# Confidential Information of ARM, Inc.
# Use subject to ARM license.
# Copyright (c) 2018 ARM, Inc.

# ACI Version r9p1

# Reifier 3.1.1

VERSION 5.6 ;

BUSBITCHARS "[]" ;

#name: High Speed Two Port RF RVT-HVT-RVT Compiler|40G 40nm Process, 0.741^2 BitCell
#version: r9p1
#comment: 
#configuration:  -instname "rf_2p_hse" -words 64 -bits 16 -frequency 100 -mux 1 -pipeline off -write_mask off -wp_size 8 -top_layer "m5-m9" -power_type otc -redundancy off -rcols 1 -rrows 0 -bmux on -ser none -power_gating off -retention on -ema on -atf off -cust_comment "" -bus_notation on -left_bus_delim "[" -right_bus_delim "]" -pwr_gnd_rename "vddpe:VDDPE,vddce:VDDCE,vsse:VSSE" -prefix "" -name_case upper -check_instname on -diodes on -drive 4 -corners ss_0p81v_0p81v_125c,ss_0p81v_0p81v_m40c,ffg_0p99v_0p99v_125c,ff_0p99v_0p99v_125c,ff_0p99v_0p99v_m40c,tt_0p90v_0p90v_25c
SITE rf_2p_hse
  CLASS  CORE ;
  SIZE 75.34 BY 48.695 ;
  END rf_2p_hse

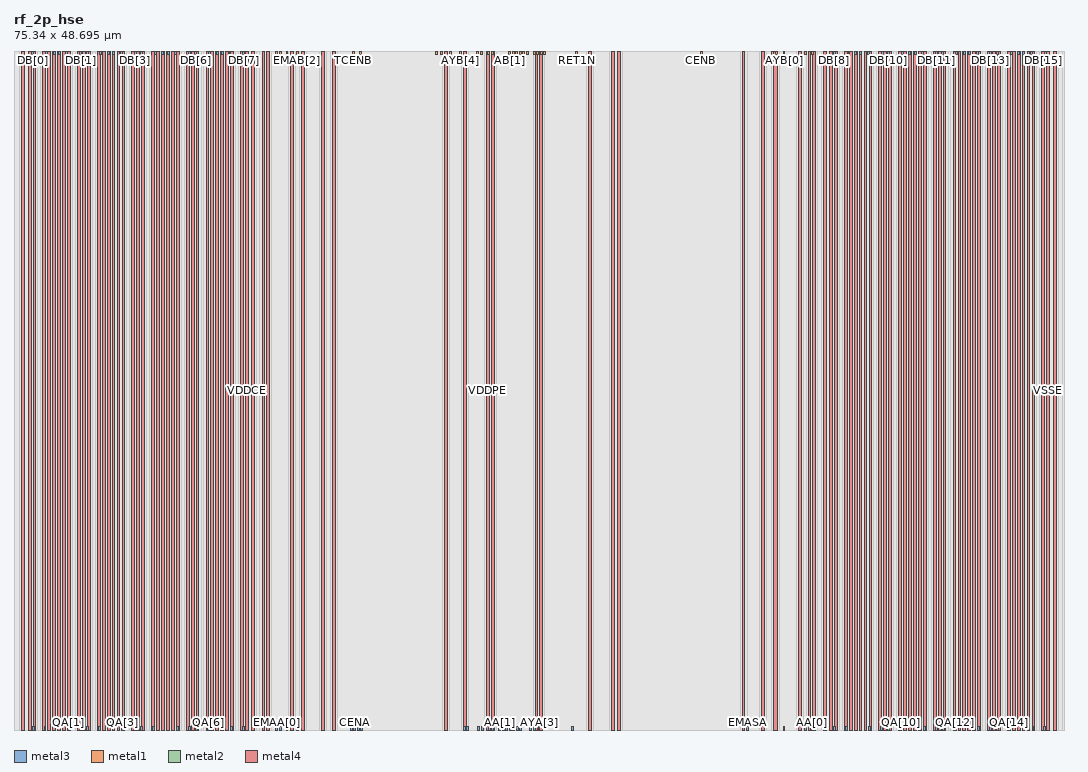
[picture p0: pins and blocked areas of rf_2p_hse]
MACRO rf_2p_hse
  FOREIGN rf_2p_hse 0 0 ;
  SYMMETRY X Y R90 ;
  SITE rf_2p_hse ;
  SIZE 75.34 BY 48.695 ;
  CLASS BLOCK ;
  PIN TDB[13]
    DIRECTION INPUT ;
    USE SIGNAL ;
    SHAPE ABUTMENT ;
    PORT
      LAYER metal3 ;
      RECT 68.49 48.445 68.63 48.695 ;
      END
    ANTENNAGATEAREA 0.009 ;
    ANTENNADIFFAREA 0.035 ;
    END TDB[13]
  PIN TDB[12]
    DIRECTION INPUT ;
    USE SIGNAL ;
    SHAPE ABUTMENT ;
    PORT
      LAYER metal3 ;
      RECT 68.11 48.445 68.25 48.695 ;
      END
    ANTENNAGATEAREA 0.009 ;
    ANTENNADIFFAREA 0.035 ;
    END TDB[12]
  PIN DYB[13]
    DIRECTION OUTPUT ;
    USE SIGNAL ;
    SHAPE ABUTMENT ;
    PORT
      LAYER metal3 ;
      RECT 69.03 48.445 69.17 48.695 ;
      END
    ANTENNADIFFAREA 0.035 ;
    END DYB[13]
  PIN DYB[12]
    DIRECTION OUTPUT ;
    USE SIGNAL ;
    SHAPE ABUTMENT ;
    PORT
      LAYER metal3 ;
      RECT 67.57 48.445 67.71 48.695 ;
      END
    ANTENNADIFFAREA 0.035 ;
    END DYB[12]
  PIN DB[13]
    DIRECTION INPUT ;
    USE SIGNAL ;
    SHAPE ABUTMENT ;
    PORT
      LAYER metal3 ;
      RECT 70.03 48.445 70.17 48.695 ;
      END
    ANTENNAGATEAREA 0.009 ;
    ANTENNADIFFAREA 0.035 ;
    END DB[13]
  PIN DB[12]
    DIRECTION INPUT ;
    USE SIGNAL ;
    SHAPE ABUTMENT ;
    PORT
      LAYER metal3 ;
      RECT 66.57 48.445 66.71 48.695 ;
      END
    ANTENNAGATEAREA 0.009 ;
    ANTENNADIFFAREA 0.035 ;
    END DB[12]
  PIN DB[14]
    DIRECTION INPUT ;
    USE SIGNAL ;
    SHAPE ABUTMENT ;
    PORT
      LAYER metal3 ;
      RECT 70.47 48.445 70.61 48.695 ;
      END
    ANTENNAGATEAREA 0.009 ;
    ANTENNADIFFAREA 0.035 ;
    END DB[14]
  PIN DB[11]
    DIRECTION INPUT ;
    USE SIGNAL ;
    SHAPE ABUTMENT ;
    PORT
      LAYER metal3 ;
      RECT 66.13 48.445 66.27 48.695 ;
      END
    ANTENNAGATEAREA 0.009 ;
    ANTENNADIFFAREA 0.035 ;
    END DB[11]
  PIN DYB[14]
    DIRECTION OUTPUT ;
    USE SIGNAL ;
    SHAPE ABUTMENT ;
    PORT
      LAYER metal3 ;
      RECT 71.47 48.445 71.61 48.695 ;
      END
    ANTENNADIFFAREA 0.035 ;
    END DYB[14]
  PIN DYB[11]
    DIRECTION OUTPUT ;
    USE SIGNAL ;
    SHAPE ABUTMENT ;
    PORT
      LAYER metal3 ;
      RECT 65.13 48.445 65.27 48.695 ;
      END
    ANTENNADIFFAREA 0.035 ;
    END DYB[11]
  PIN TDB[14]
    DIRECTION INPUT ;
    USE SIGNAL ;
    SHAPE ABUTMENT ;
    PORT
      LAYER metal3 ;
      RECT 72.01 48.445 72.15 48.695 ;
      END
    ANTENNAGATEAREA 0.009 ;
    ANTENNADIFFAREA 0.035 ;
    END TDB[14]
  PIN TDB[11]
    DIRECTION INPUT ;
    USE SIGNAL ;
    SHAPE ABUTMENT ;
    PORT
      LAYER metal3 ;
      RECT 64.59 48.445 64.73 48.695 ;
      END
    ANTENNAGATEAREA 0.009 ;
    ANTENNADIFFAREA 0.035 ;
    END TDB[11]
  PIN TDB[15]
    DIRECTION INPUT ;
    USE SIGNAL ;
    SHAPE ABUTMENT ;
    PORT
      LAYER metal3 ;
      RECT 72.39 48.445 72.53 48.695 ;
      END
    ANTENNAGATEAREA 0.009 ;
    ANTENNADIFFAREA 0.035 ;
    END TDB[15]
  PIN TDB[10]
    DIRECTION INPUT ;
    USE SIGNAL ;
    SHAPE ABUTMENT ;
    PORT
      LAYER metal3 ;
      RECT 64.21 48.445 64.35 48.695 ;
      END
    ANTENNAGATEAREA 0.009 ;
    ANTENNADIFFAREA 0.035 ;
    END TDB[10]
  PIN DYB[15]
    DIRECTION OUTPUT ;
    USE SIGNAL ;
    SHAPE ABUTMENT ;
    PORT
      LAYER metal3 ;
      RECT 72.93 48.445 73.07 48.695 ;
      END
    ANTENNADIFFAREA 0.035 ;
    END DYB[15]
  PIN DYB[10]
    DIRECTION OUTPUT ;
    USE SIGNAL ;
    SHAPE ABUTMENT ;
    PORT
      LAYER metal3 ;
      RECT 63.67 48.445 63.81 48.695 ;
      END
    ANTENNADIFFAREA 0.035 ;
    END DYB[10]
  PIN DB[15]
    DIRECTION INPUT ;
    USE SIGNAL ;
    SHAPE ABUTMENT ;
    PORT
      LAYER metal3 ;
      RECT 73.93 48.445 74.07 48.695 ;
      END
    ANTENNAGATEAREA 0.009 ;
    ANTENNADIFFAREA 0.035 ;
    END DB[15]
  PIN DB[10]
    DIRECTION INPUT ;
    USE SIGNAL ;
    SHAPE ABUTMENT ;
    PORT
      LAYER metal3 ;
      RECT 62.67 48.445 62.81 48.695 ;
      END
    ANTENNAGATEAREA 0.009 ;
    ANTENNADIFFAREA 0.035 ;
    END DB[10]
  PIN TQA[0]
    DIRECTION INPUT ;
    USE SIGNAL ;
    SHAPE ABUTMENT ;
    PORT
      LAYER metal1 ;
      RECT 1.3 0.0 1.44 0.25 ;
      LAYER metal2 ;
      RECT 1.3 0.0 1.44 0.25 ;
      LAYER metal3 ;
      RECT 1.3 0.0 1.44 0.25 ;
      END
    ANTENNAGATEAREA 0.009 ;
    ANTENNADIFFAREA 0.035 ;
    END TQA[0]
  PIN DB[9]
    DIRECTION INPUT ;
    USE SIGNAL ;
    SHAPE ABUTMENT ;
    PORT
      LAYER metal3 ;
      RECT 62.23 48.445 62.37 48.695 ;
      END
    ANTENNAGATEAREA 0.009 ;
    ANTENNADIFFAREA 0.035 ;
    END DB[9]
  PIN QA[0]
    DIRECTION OUTPUT ;
    USE SIGNAL ;
    SHAPE ABUTMENT ;
    PORT
      LAYER metal1 ;
      RECT 2.155 0.0 2.295 0.25 ;
      LAYER metal2 ;
      RECT 2.155 0.0 2.295 0.25 ;
      LAYER metal3 ;
      RECT 2.155 0.0 2.295 0.25 ;
      END
    ANTENNADIFFAREA 0.035 ;
    END QA[0]
  PIN DYB[9]
    DIRECTION OUTPUT ;
    USE SIGNAL ;
    SHAPE ABUTMENT ;
    PORT
      LAYER metal3 ;
      RECT 61.23 48.445 61.37 48.695 ;
      END
    ANTENNADIFFAREA 0.035 ;
    END DYB[9]
  PIN QA[1]
    DIRECTION OUTPUT ;
    USE SIGNAL ;
    SHAPE ABUTMENT ;
    PORT
      LAYER metal1 ;
      RECT 3.845 0.0 3.985 0.25 ;
      LAYER metal2 ;
      RECT 3.845 0.0 3.985 0.25 ;
      LAYER metal3 ;
      RECT 3.845 0.0 3.985 0.25 ;
      END
    ANTENNADIFFAREA 0.035 ;
    END QA[1]
  PIN TDB[9]
    DIRECTION INPUT ;
    USE SIGNAL ;
    SHAPE ABUTMENT ;
    PORT
      LAYER metal3 ;
      RECT 60.69 48.445 60.83 48.695 ;
      END
    ANTENNAGATEAREA 0.009 ;
    ANTENNADIFFAREA 0.035 ;
    END TDB[9]
  PIN TQA[1]
    DIRECTION INPUT ;
    USE SIGNAL ;
    SHAPE ABUTMENT ;
    PORT
      LAYER metal1 ;
      RECT 4.7 0.0 4.84 0.25 ;
      LAYER metal2 ;
      RECT 4.7 0.0 4.84 0.25 ;
      LAYER metal3 ;
      RECT 4.7 0.0 4.84 0.25 ;
      END
    ANTENNAGATEAREA 0.009 ;
    ANTENNADIFFAREA 0.035 ;
    END TQA[1]
  PIN TDB[8]
    DIRECTION INPUT ;
    USE SIGNAL ;
    SHAPE ABUTMENT ;
    PORT
      LAYER metal3 ;
      RECT 60.31 48.445 60.45 48.695 ;
      END
    ANTENNAGATEAREA 0.009 ;
    ANTENNADIFFAREA 0.035 ;
    END TDB[8]
  PIN TQA[2]
    DIRECTION INPUT ;
    USE SIGNAL ;
    SHAPE ABUTMENT ;
    PORT
      LAYER metal1 ;
      RECT 5.2 0.0 5.34 0.25 ;
      LAYER metal2 ;
      RECT 5.2 0.0 5.34 0.25 ;
      LAYER metal3 ;
      RECT 5.2 0.0 5.34 0.25 ;
      END
    ANTENNAGATEAREA 0.009 ;
    ANTENNADIFFAREA 0.035 ;
    END TQA[2]
  PIN DYB[8]
    DIRECTION OUTPUT ;
    USE SIGNAL ;
    SHAPE ABUTMENT ;
    PORT
      LAYER metal3 ;
      RECT 59.77 48.445 59.91 48.695 ;
      END
    ANTENNADIFFAREA 0.035 ;
    END DYB[8]
  PIN QA[2]
    DIRECTION OUTPUT ;
    USE SIGNAL ;
    SHAPE ABUTMENT ;
    PORT
      LAYER metal1 ;
      RECT 6.055 0.0 6.195 0.25 ;
      LAYER metal2 ;
      RECT 6.055 0.0 6.195 0.25 ;
      LAYER metal3 ;
      RECT 6.055 0.0 6.195 0.25 ;
      END
    ANTENNADIFFAREA 0.035 ;
    END QA[2]
  PIN DB[8]
    DIRECTION INPUT ;
    USE SIGNAL ;
    SHAPE ABUTMENT ;
    PORT
      LAYER metal3 ;
      RECT 58.77 48.445 58.91 48.695 ;
      END
    ANTENNAGATEAREA 0.009 ;
    ANTENNADIFFAREA 0.035 ;
    END DB[8]
  PIN QA[3]
    DIRECTION OUTPUT ;
    USE SIGNAL ;
    SHAPE ABUTMENT ;
    PORT
      LAYER metal1 ;
      RECT 7.745 0.0 7.885 0.25 ;
      LAYER metal2 ;
      RECT 7.745 0.0 7.885 0.25 ;
      LAYER metal3 ;
      RECT 7.745 0.0 7.885 0.25 ;
      END
    ANTENNADIFFAREA 0.035 ;
    END QA[3]
  PIN AB[0]
    DIRECTION INPUT ;
    USE SIGNAL ;
    SHAPE ABUTMENT ;
    PORT
      LAYER metal3 ;
      RECT 57.21 48.445 57.35 48.695 ;
      LAYER metal2 ;
      RECT 57.21 48.445 57.35 48.695 ;
      LAYER metal1 ;
      RECT 57.21 48.445 57.35 48.695 ;
      END
    ANTENNAGATEAREA 0.009 ;
    ANTENNADIFFAREA 0.035 ;
    END AB[0]
  PIN TQA[3]
    DIRECTION INPUT ;
    USE SIGNAL ;
    SHAPE ABUTMENT ;
    PORT
      LAYER metal1 ;
      RECT 8.6 0.0 8.74 0.25 ;
      LAYER metal2 ;
      RECT 8.6 0.0 8.74 0.25 ;
      LAYER metal3 ;
      RECT 8.6 0.0 8.74 0.25 ;
      END
    ANTENNAGATEAREA 0.009 ;
    ANTENNADIFFAREA 0.035 ;
    END TQA[3]
  PIN TAB[0]
    DIRECTION INPUT ;
    USE SIGNAL ;
    SHAPE ABUTMENT ;
    PORT
      LAYER metal3 ;
      RECT 56.71 48.445 56.85 48.695 ;
      LAYER metal2 ;
      RECT 56.71 48.445 56.85 48.695 ;
      LAYER metal1 ;
      RECT 56.71 48.445 56.85 48.695 ;
      END
    ANTENNAGATEAREA 0.009 ;
    ANTENNADIFFAREA 0.035 ;
    END TAB[0]
  PIN TQA[4]
    DIRECTION INPUT ;
    USE SIGNAL ;
    SHAPE ABUTMENT ;
    PORT
      LAYER metal1 ;
      RECT 9.1 0.0 9.24 0.25 ;
      LAYER metal2 ;
      RECT 9.1 0.0 9.24 0.25 ;
      LAYER metal3 ;
      RECT 9.1 0.0 9.24 0.25 ;
      END
    ANTENNAGATEAREA 0.009 ;
    ANTENNADIFFAREA 0.035 ;
    END TQA[4]
  PIN AYB[0]
    DIRECTION OUTPUT ;
    USE SIGNAL ;
    SHAPE ABUTMENT ;
    PORT
      LAYER metal3 ;
      RECT 55.18 48.445 55.32 48.695 ;
      LAYER metal2 ;
      RECT 55.18 48.445 55.32 48.695 ;
      LAYER metal1 ;
      RECT 55.18 48.445 55.32 48.695 ;
      END
    ANTENNADIFFAREA 0.035 ;
    END AYB[0]
  PIN QA[4]
    DIRECTION OUTPUT ;
    USE SIGNAL ;
    SHAPE ABUTMENT ;
    PORT
      LAYER metal1 ;
      RECT 9.955 0.0 10.095 0.25 ;
      LAYER metal2 ;
      RECT 9.955 0.0 10.095 0.25 ;
      LAYER metal3 ;
      RECT 9.955 0.0 10.095 0.25 ;
      END
    ANTENNADIFFAREA 0.035 ;
    END QA[4]
  PIN EMAWB[0]
    DIRECTION INPUT ;
    USE SIGNAL ;
    SHAPE ABUTMENT ;
    PORT
      LAYER metal3 ;
      RECT 54.63 48.445 54.77 48.695 ;
      LAYER metal2 ;
      RECT 54.63 48.445 54.77 48.695 ;
      LAYER metal1 ;
      RECT 54.63 48.445 54.77 48.695 ;
      END
    ANTENNAGATEAREA 0.009 ;
    ANTENNADIFFAREA 0.035 ;
    END EMAWB[0]
  PIN QA[5]
    DIRECTION OUTPUT ;
    USE SIGNAL ;
    SHAPE ABUTMENT ;
    PORT
      LAYER metal1 ;
      RECT 11.645 0.0 11.785 0.25 ;
      LAYER metal2 ;
      RECT 11.645 0.0 11.785 0.25 ;
      LAYER metal3 ;
      RECT 11.645 0.0 11.785 0.25 ;
      END
    ANTENNADIFFAREA 0.035 ;
    END QA[5]
  PIN EMAWB[1]
    DIRECTION INPUT ;
    USE SIGNAL ;
    SHAPE ABUTMENT ;
    PORT
      LAYER metal3 ;
      RECT 54.38 48.445 54.52 48.695 ;
      LAYER metal2 ;
      RECT 54.38 48.445 54.52 48.695 ;
      LAYER metal1 ;
      RECT 54.38 48.445 54.52 48.695 ;
      END
    ANTENNAGATEAREA 0.009 ;
    ANTENNADIFFAREA 0.035 ;
    END EMAWB[1]
  PIN TQA[5]
    DIRECTION INPUT ;
    USE SIGNAL ;
    SHAPE ABUTMENT ;
    PORT
      LAYER metal1 ;
      RECT 12.5 0.0 12.64 0.25 ;
      LAYER metal2 ;
      RECT 12.5 0.0 12.64 0.25 ;
      LAYER metal3 ;
      RECT 12.5 0.0 12.64 0.25 ;
      END
    ANTENNAGATEAREA 0.009 ;
    ANTENNADIFFAREA 0.035 ;
    END TQA[5]
  PIN CENB
    DIRECTION INPUT ;
    USE SIGNAL ;
    SHAPE ABUTMENT ;
    PORT
      LAYER metal3 ;
      RECT 49.235 48.445 49.375 48.695 ;
      LAYER metal2 ;
      RECT 49.235 48.445 49.375 48.695 ;
      LAYER metal1 ;
      RECT 49.235 48.445 49.375 48.695 ;
      END
    ANTENNAGATEAREA 0.009 ;
    ANTENNADIFFAREA 0.035 ;
    END CENB
  PIN TQA[6]
    DIRECTION INPUT ;
    USE SIGNAL ;
    SHAPE ABUTMENT ;
    PORT
      LAYER metal1 ;
      RECT 13.0 0.0 13.14 0.25 ;
      LAYER metal2 ;
      RECT 13.0 0.0 13.14 0.25 ;
      LAYER metal3 ;
      RECT 13.0 0.0 13.14 0.25 ;
      END
    ANTENNAGATEAREA 0.009 ;
    ANTENNADIFFAREA 0.035 ;
    END TQA[6]
  PIN RET1N
    DIRECTION INPUT ;
    USE SIGNAL ;
    SHAPE ABUTMENT ;
    PORT
      LAYER metal3 ;
      RECT 40.3 48.445 40.44 48.695 ;
      LAYER metal2 ;
      RECT 40.3 48.445 40.44 48.695 ;
      LAYER metal1 ;
      RECT 40.3 48.445 40.44 48.695 ;
      END
    ANTENNAGATEAREA 0.009 ;
    ANTENNADIFFAREA 0.035 ;
    END RET1N
  PIN QA[6]
    DIRECTION OUTPUT ;
    USE SIGNAL ;
    SHAPE ABUTMENT ;
    PORT
      LAYER metal1 ;
      RECT 13.855 0.0 13.995 0.25 ;
      LAYER metal2 ;
      RECT 13.855 0.0 13.995 0.25 ;
      LAYER metal3 ;
      RECT 13.855 0.0 13.995 0.25 ;
      END
    ANTENNADIFFAREA 0.035 ;
    END QA[6]
  PIN TENB
    DIRECTION INPUT ;
    USE SIGNAL ;
    SHAPE ABUTMENT ;
    PORT
      LAYER metal3 ;
      RECT 38.0 48.445 38.14 48.695 ;
      LAYER metal2 ;
      RECT 38.0 48.445 38.14 48.695 ;
      LAYER metal1 ;
      RECT 38.0 48.445 38.14 48.695 ;
      END
    ANTENNAGATEAREA 0.009 ;
    ANTENNADIFFAREA 0.035 ;
    END TENB
  PIN QA[7]
    DIRECTION OUTPUT ;
    USE SIGNAL ;
    SHAPE ABUTMENT ;
    PORT
      LAYER metal1 ;
      RECT 15.545 0.0 15.685 0.25 ;
      LAYER metal2 ;
      RECT 15.545 0.0 15.685 0.25 ;
      LAYER metal3 ;
      RECT 15.545 0.0 15.685 0.25 ;
      END
    ANTENNADIFFAREA 0.035 ;
    END QA[7]
  PIN AYB[3]
    DIRECTION OUTPUT ;
    USE SIGNAL ;
    SHAPE ABUTMENT ;
    PORT
      LAYER metal3 ;
      RECT 37.75 48.445 37.89 48.695 ;
      LAYER metal2 ;
      RECT 37.75 48.445 37.89 48.695 ;
      LAYER metal1 ;
      RECT 37.75 48.445 37.89 48.695 ;
      END
    ANTENNADIFFAREA 0.035 ;
    END AYB[3]
  PIN TQA[7]
    DIRECTION INPUT ;
    USE SIGNAL ;
    SHAPE ABUTMENT ;
    PORT
      LAYER metal1 ;
      RECT 16.4 0.0 16.54 0.25 ;
      LAYER metal2 ;
      RECT 16.4 0.0 16.54 0.25 ;
      LAYER metal3 ;
      RECT 16.4 0.0 16.54 0.25 ;
      END
    ANTENNAGATEAREA 0.009 ;
    ANTENNADIFFAREA 0.035 ;
    END TQA[7]
  PIN AYB[2]
    DIRECTION OUTPUT ;
    USE SIGNAL ;
    SHAPE ABUTMENT ;
    PORT
      LAYER metal3 ;
      RECT 37.5 48.445 37.64 48.695 ;
      LAYER metal2 ;
      RECT 37.5 48.445 37.64 48.695 ;
      LAYER metal1 ;
      RECT 37.5 48.445 37.64 48.695 ;
      END
    ANTENNADIFFAREA 0.035 ;
    END AYB[2]
  PIN EMAA[0]
    DIRECTION INPUT ;
    USE SIGNAL ;
    SHAPE ABUTMENT ;
    PORT
      LAYER metal1 ;
      RECT 18.77 0.0 18.91 0.25 ;
      LAYER metal2 ;
      RECT 18.77 0.0 18.91 0.25 ;
      LAYER metal3 ;
      RECT 18.77 0.0 18.91 0.25 ;
      END
    ANTENNAGATEAREA 0.009 ;
    ANTENNADIFFAREA 0.035 ;
    END EMAA[0]
  PIN AYB[1]
    DIRECTION OUTPUT ;
    USE SIGNAL ;
    SHAPE ABUTMENT ;
    PORT
      LAYER metal3 ;
      RECT 37.25 48.445 37.39 48.695 ;
      LAYER metal2 ;
      RECT 37.25 48.445 37.39 48.695 ;
      LAYER metal1 ;
      RECT 37.25 48.445 37.39 48.695 ;
      END
    ANTENNADIFFAREA 0.035 ;
    END AYB[1]
  PIN EMAA[1]
    DIRECTION INPUT ;
    USE SIGNAL ;
    SHAPE ABUTMENT ;
    PORT
      LAYER metal1 ;
      RECT 19.02 0.0 19.16 0.25 ;
      LAYER metal2 ;
      RECT 19.02 0.0 19.16 0.25 ;
      LAYER metal3 ;
      RECT 19.02 0.0 19.16 0.25 ;
      END
    ANTENNAGATEAREA 0.009 ;
    ANTENNADIFFAREA 0.035 ;
    END EMAA[1]
  PIN TAB[3]
    DIRECTION INPUT ;
    USE SIGNAL ;
    SHAPE ABUTMENT ;
    PORT
      LAYER metal3 ;
      RECT 36.75 48.445 36.89 48.695 ;
      LAYER metal2 ;
      RECT 36.75 48.445 36.89 48.695 ;
      LAYER metal1 ;
      RECT 36.75 48.445 36.89 48.695 ;
      END
    ANTENNAGATEAREA 0.009 ;
    ANTENNADIFFAREA 0.035 ;
    END TAB[3]
  PIN STOVA
    DIRECTION INPUT ;
    USE SIGNAL ;
    SHAPE ABUTMENT ;
    PORT
      LAYER metal1 ;
      RECT 19.52 0.0 19.66 0.25 ;
      LAYER metal2 ;
      RECT 19.52 0.0 19.66 0.25 ;
      LAYER metal3 ;
      RECT 19.52 0.0 19.66 0.25 ;
      END
    ANTENNAGATEAREA 0.009 ;
    ANTENNADIFFAREA 0.035 ;
    END STOVA
  PIN TAB[2]
    DIRECTION INPUT ;
    USE SIGNAL ;
    SHAPE ABUTMENT ;
    PORT
      LAYER metal3 ;
      RECT 36.5 48.445 36.64 48.695 ;
      LAYER metal2 ;
      RECT 36.5 48.445 36.64 48.695 ;
      LAYER metal1 ;
      RECT 36.5 48.445 36.64 48.695 ;
      END
    ANTENNAGATEAREA 0.009 ;
    ANTENNADIFFAREA 0.035 ;
    END TAB[2]
  PIN EMAA[2]
    DIRECTION INPUT ;
    USE SIGNAL ;
    SHAPE ABUTMENT ;
    PORT
      LAYER metal1 ;
      RECT 20.27 0.0 20.41 0.25 ;
      LAYER metal2 ;
      RECT 20.27 0.0 20.41 0.25 ;
      LAYER metal3 ;
      RECT 20.27 0.0 20.41 0.25 ;
      END
    ANTENNAGATEAREA 0.009 ;
    ANTENNADIFFAREA 0.035 ;
    END EMAA[2]
  PIN TAB[1]
    DIRECTION INPUT ;
    USE SIGNAL ;
    SHAPE ABUTMENT ;
    PORT
      LAYER metal3 ;
      RECT 36.25 48.445 36.39 48.695 ;
      LAYER metal2 ;
      RECT 36.25 48.445 36.39 48.695 ;
      LAYER metal1 ;
      RECT 36.25 48.445 36.39 48.695 ;
      END
    ANTENNAGATEAREA 0.009 ;
    ANTENNADIFFAREA 0.035 ;
    END TAB[1]
  PIN TCENA
    DIRECTION INPUT ;
    USE SIGNAL ;
    SHAPE ABUTMENT ;
    PORT
      LAYER metal1 ;
      RECT 24.14 0.0 24.28 0.25 ;
      LAYER metal2 ;
      RECT 24.14 0.0 24.28 0.25 ;
      LAYER metal3 ;
      RECT 24.14 0.0 24.28 0.25 ;
      END
    ANTENNAGATEAREA 0.009 ;
    ANTENNADIFFAREA 0.035 ;
    END TCENA
  PIN AB[3]
    DIRECTION INPUT ;
    USE SIGNAL ;
    SHAPE ABUTMENT ;
    PORT
      LAYER metal3 ;
      RECT 36.0 48.445 36.14 48.695 ;
      LAYER metal2 ;
      RECT 36.0 48.445 36.14 48.695 ;
      LAYER metal1 ;
      RECT 36.0 48.445 36.14 48.695 ;
      END
    ANTENNAGATEAREA 0.009 ;
    ANTENNADIFFAREA 0.035 ;
    END AB[3]
  PIN CENA
    DIRECTION INPUT ;
    USE SIGNAL ;
    SHAPE ABUTMENT ;
    PORT
      LAYER metal1 ;
      RECT 24.39 0.0 24.53 0.25 ;
      LAYER metal2 ;
      RECT 24.39 0.0 24.53 0.25 ;
      LAYER metal3 ;
      RECT 24.39 0.0 24.53 0.25 ;
      END
    ANTENNAGATEAREA 0.009 ;
    ANTENNADIFFAREA 0.035 ;
    END CENA
  PIN AB[2]
    DIRECTION INPUT ;
    USE SIGNAL ;
    SHAPE ABUTMENT ;
    PORT
      LAYER metal3 ;
      RECT 35.75 48.445 35.89 48.695 ;
      LAYER metal2 ;
      RECT 35.75 48.445 35.89 48.695 ;
      LAYER metal1 ;
      RECT 35.75 48.445 35.89 48.695 ;
      END
    ANTENNAGATEAREA 0.009 ;
    ANTENNADIFFAREA 0.035 ;
    END AB[2]
  PIN CLKA
    DIRECTION INPUT ;
    USE SIGNAL ;
    SHAPE ABUTMENT ;
    PORT
      LAYER metal1 ;
      RECT 24.64 0.0 24.78 0.25 ;
      LAYER metal2 ;
      RECT 24.64 0.0 24.78 0.25 ;
      LAYER metal3 ;
      RECT 24.64 0.0 24.78 0.25 ;
      END
    ANTENNAGATEAREA 0.009 ;
    ANTENNADIFFAREA 0.035 ;
    END CLKA
  PIN AB[1]
    DIRECTION INPUT ;
    USE SIGNAL ;
    SHAPE ABUTMENT ;
    PORT
      LAYER metal3 ;
      RECT 35.5 48.445 35.64 48.695 ;
      LAYER metal2 ;
      RECT 35.5 48.445 35.64 48.695 ;
      LAYER metal1 ;
      RECT 35.5 48.445 35.64 48.695 ;
      END
    ANTENNAGATEAREA 0.009 ;
    ANTENNADIFFAREA 0.035 ;
    END AB[1]
  PIN CENYA
    DIRECTION OUTPUT ;
    USE SIGNAL ;
    SHAPE ABUTMENT ;
    PORT
      LAYER metal1 ;
      RECT 24.89 0.0 25.03 0.25 ;
      LAYER metal2 ;
      RECT 24.89 0.0 25.03 0.25 ;
      LAYER metal3 ;
      RECT 24.89 0.0 25.03 0.25 ;
      END
    ANTENNADIFFAREA 0.035 ;
    END CENYA
  PIN AB[5]
    DIRECTION INPUT ;
    USE SIGNAL ;
    SHAPE ABUTMENT ;
    PORT
      LAYER metal3 ;
      RECT 34.25 48.445 34.39 48.695 ;
      LAYER metal2 ;
      RECT 34.25 48.445 34.39 48.695 ;
      LAYER metal1 ;
      RECT 34.25 48.445 34.39 48.695 ;
      END
    ANTENNAGATEAREA 0.009 ;
    ANTENNADIFFAREA 0.035 ;
    END AB[5]
  PIN AYA[5]
    DIRECTION OUTPUT ;
    USE SIGNAL ;
    SHAPE ABUTMENT ;
    PORT
      LAYER metal1 ;
      RECT 32.225 0.0 32.365 0.25 ;
      LAYER metal2 ;
      RECT 32.225 0.0 32.365 0.25 ;
      LAYER metal3 ;
      RECT 32.225 0.0 32.365 0.25 ;
      END
    ANTENNADIFFAREA 0.035 ;
    END AYA[5]
  PIN AB[4]
    DIRECTION INPUT ;
    USE SIGNAL ;
    SHAPE ABUTMENT ;
    PORT
      LAYER metal3 ;
      RECT 34.0 48.445 34.14 48.695 ;
      LAYER metal2 ;
      RECT 34.0 48.445 34.14 48.695 ;
      LAYER metal1 ;
      RECT 34.0 48.445 34.14 48.695 ;
      END
    ANTENNAGATEAREA 0.009 ;
    ANTENNADIFFAREA 0.035 ;
    END AB[4]
  PIN AYA[4]
    DIRECTION OUTPUT ;
    USE SIGNAL ;
    SHAPE ABUTMENT ;
    PORT
      LAYER metal1 ;
      RECT 32.475 0.0 32.615 0.25 ;
      LAYER metal2 ;
      RECT 32.475 0.0 32.615 0.25 ;
      LAYER metal3 ;
      RECT 32.475 0.0 32.615 0.25 ;
      END
    ANTENNADIFFAREA 0.035 ;
    END AYA[4]
  PIN TAB[5]
    DIRECTION INPUT ;
    USE SIGNAL ;
    SHAPE ABUTMENT ;
    PORT
      LAYER metal3 ;
      RECT 33.5 48.445 33.64 48.695 ;
      LAYER metal2 ;
      RECT 33.5 48.445 33.64 48.695 ;
      LAYER metal1 ;
      RECT 33.5 48.445 33.64 48.695 ;
      END
    ANTENNAGATEAREA 0.009 ;
    ANTENNADIFFAREA 0.035 ;
    END TAB[5]
  PIN TAA[4]
    DIRECTION INPUT ;
    USE SIGNAL ;
    SHAPE ABUTMENT ;
    PORT
      LAYER metal1 ;
      RECT 33.29 0.0 33.43 0.25 ;
      LAYER metal2 ;
      RECT 33.29 0.0 33.43 0.25 ;
      LAYER metal3 ;
      RECT 33.29 0.0 33.43 0.25 ;
      END
    ANTENNAGATEAREA 0.009 ;
    ANTENNADIFFAREA 0.035 ;
    END TAA[4]
  PIN TAB[4]
    DIRECTION INPUT ;
    USE SIGNAL ;
    SHAPE ABUTMENT ;
    PORT
      LAYER metal3 ;
      RECT 33.22 48.445 33.36 48.695 ;
      LAYER metal2 ;
      RECT 33.22 48.445 33.36 48.695 ;
      LAYER metal1 ;
      RECT 33.22 48.445 33.36 48.695 ;
      END
    ANTENNAGATEAREA 0.009 ;
    ANTENNADIFFAREA 0.035 ;
    END TAB[4]
  PIN TAA[5]
    DIRECTION INPUT ;
    USE SIGNAL ;
    SHAPE ABUTMENT ;
    PORT
      LAYER metal1 ;
      RECT 33.54 0.0 33.68 0.25 ;
      LAYER metal2 ;
      RECT 33.54 0.0 33.68 0.25 ;
      LAYER metal3 ;
      RECT 33.54 0.0 33.68 0.25 ;
      END
    ANTENNAGATEAREA 0.009 ;
    ANTENNADIFFAREA 0.035 ;
    END TAA[5]
  PIN AYB[4]
    DIRECTION OUTPUT ;
    USE SIGNAL ;
    SHAPE ABUTMENT ;
    PORT
      LAYER metal3 ;
      RECT 31.97 48.445 32.11 48.695 ;
      LAYER metal2 ;
      RECT 31.97 48.445 32.11 48.695 ;
      LAYER metal1 ;
      RECT 31.97 48.445 32.11 48.695 ;
      END
    ANTENNADIFFAREA 0.035 ;
    END AYB[4]
  PIN AA[4]
    DIRECTION INPUT ;
    USE SIGNAL ;
    SHAPE ABUTMENT ;
    PORT
      LAYER metal1 ;
      RECT 34.04 0.0 34.18 0.25 ;
      LAYER metal2 ;
      RECT 34.04 0.0 34.18 0.25 ;
      LAYER metal3 ;
      RECT 34.04 0.0 34.18 0.25 ;
      END
    ANTENNAGATEAREA 0.009 ;
    ANTENNADIFFAREA 0.035 ;
    END AA[4]
  PIN AYB[5]
    DIRECTION OUTPUT ;
    USE SIGNAL ;
    SHAPE ABUTMENT ;
    PORT
      LAYER metal3 ;
      RECT 31.22 48.445 31.36 48.695 ;
      LAYER metal2 ;
      RECT 31.22 48.445 31.36 48.695 ;
      LAYER metal1 ;
      RECT 31.22 48.445 31.36 48.695 ;
      END
    ANTENNADIFFAREA 0.035 ;
    END AYB[5]
  PIN AA[5]
    DIRECTION INPUT ;
    USE SIGNAL ;
    SHAPE ABUTMENT ;
    PORT
      LAYER metal1 ;
      RECT 34.29 0.0 34.43 0.25 ;
      LAYER metal2 ;
      RECT 34.29 0.0 34.43 0.25 ;
      LAYER metal3 ;
      RECT 34.29 0.0 34.43 0.25 ;
      END
    ANTENNAGATEAREA 0.009 ;
    ANTENNADIFFAREA 0.035 ;
    END AA[5]
  PIN COLLDISN
    DIRECTION INPUT ;
    USE SIGNAL ;
    SHAPE ABUTMENT ;
    PORT
      LAYER metal3 ;
      RECT 30.61 48.445 30.75 48.695 ;
      LAYER metal2 ;
      RECT 30.61 48.445 30.75 48.695 ;
      LAYER metal1 ;
      RECT 30.61 48.445 30.75 48.695 ;
      END
    ANTENNAGATEAREA 0.009 ;
    ANTENNADIFFAREA 0.035 ;
    END COLLDISN
  PIN AA[1]
    DIRECTION INPUT ;
    USE SIGNAL ;
    SHAPE ABUTMENT ;
    PORT
      LAYER metal1 ;
      RECT 34.79 0.0 34.93 0.25 ;
      LAYER metal2 ;
      RECT 34.79 0.0 34.93 0.25 ;
      LAYER metal3 ;
      RECT 34.79 0.0 34.93 0.25 ;
      END
    ANTENNAGATEAREA 0.009 ;
    ANTENNADIFFAREA 0.035 ;
    END AA[1]
  PIN CLKB
    DIRECTION INPUT ;
    USE SIGNAL ;
    SHAPE ABUTMENT ;
    PORT
      LAYER metal3 ;
      RECT 30.215 48.445 30.355 48.695 ;
      LAYER metal2 ;
      RECT 30.215 48.445 30.355 48.695 ;
      LAYER metal1 ;
      RECT 30.215 48.445 30.355 48.695 ;
      END
    ANTENNAGATEAREA 0.009 ;
    ANTENNADIFFAREA 0.035 ;
    END CLKB
  PIN AA[2]
    DIRECTION INPUT ;
    USE SIGNAL ;
    SHAPE ABUTMENT ;
    PORT
      LAYER metal1 ;
      RECT 35.04 0.0 35.18 0.25 ;
      LAYER metal2 ;
      RECT 35.04 0.0 35.18 0.25 ;
      LAYER metal3 ;
      RECT 35.04 0.0 35.18 0.25 ;
      END
    ANTENNAGATEAREA 0.009 ;
    ANTENNADIFFAREA 0.035 ;
    END AA[2]
  PIN CENYB
    DIRECTION OUTPUT ;
    USE SIGNAL ;
    SHAPE ABUTMENT ;
    PORT
      LAYER metal3 ;
      RECT 24.79 48.445 24.93 48.695 ;
      LAYER metal2 ;
      RECT 24.79 48.445 24.93 48.695 ;
      LAYER metal1 ;
      RECT 24.79 48.445 24.93 48.695 ;
      END
    ANTENNADIFFAREA 0.035 ;
    END CENYB
  PIN AA[3]
    DIRECTION INPUT ;
    USE SIGNAL ;
    SHAPE ABUTMENT ;
    PORT
      LAYER metal1 ;
      RECT 35.29 0.0 35.43 0.25 ;
      LAYER metal2 ;
      RECT 35.29 0.0 35.43 0.25 ;
      LAYER metal3 ;
      RECT 35.29 0.0 35.43 0.25 ;
      END
    ANTENNAGATEAREA 0.009 ;
    ANTENNADIFFAREA 0.035 ;
    END AA[3]
  PIN TCENB
    DIRECTION INPUT ;
    USE SIGNAL ;
    SHAPE ABUTMENT ;
    PORT
      LAYER metal3 ;
      RECT 24.26 48.445 24.4 48.695 ;
      LAYER metal2 ;
      RECT 24.26 48.445 24.4 48.695 ;
      LAYER metal1 ;
      RECT 24.26 48.445 24.4 48.695 ;
      END
    ANTENNAGATEAREA 0.009 ;
    ANTENNADIFFAREA 0.035 ;
    END TCENB
  PIN TAA[1]
    DIRECTION INPUT ;
    USE SIGNAL ;
    SHAPE ABUTMENT ;
    PORT
      LAYER metal1 ;
      RECT 35.54 0.0 35.68 0.25 ;
      LAYER metal2 ;
      RECT 35.54 0.0 35.68 0.25 ;
      LAYER metal3 ;
      RECT 35.54 0.0 35.68 0.25 ;
      END
    ANTENNAGATEAREA 0.009 ;
    ANTENNADIFFAREA 0.035 ;
    END TAA[1]
  PIN EMAB[2]
    DIRECTION INPUT ;
    USE SIGNAL ;
    SHAPE ABUTMENT ;
    PORT
      LAYER metal3 ;
      RECT 20.27 48.445 20.41 48.695 ;
      LAYER metal2 ;
      RECT 20.27 48.445 20.41 48.695 ;
      LAYER metal1 ;
      RECT 20.27 48.445 20.41 48.695 ;
      END
    ANTENNAGATEAREA 0.009 ;
    ANTENNADIFFAREA 0.035 ;
    END EMAB[2]
  PIN TAA[2]
    DIRECTION INPUT ;
    USE SIGNAL ;
    SHAPE ABUTMENT ;
    PORT
      LAYER metal1 ;
      RECT 35.79 0.0 35.93 0.25 ;
      LAYER metal2 ;
      RECT 35.79 0.0 35.93 0.25 ;
      LAYER metal3 ;
      RECT 35.79 0.0 35.93 0.25 ;
      END
    ANTENNAGATEAREA 0.009 ;
    ANTENNADIFFAREA 0.035 ;
    END TAA[2]
  PIN STOVB
    DIRECTION INPUT ;
    USE SIGNAL ;
    SHAPE ABUTMENT ;
    PORT
      LAYER metal3 ;
      RECT 19.52 48.445 19.66 48.695 ;
      LAYER metal2 ;
      RECT 19.52 48.445 19.66 48.695 ;
      LAYER metal1 ;
      RECT 19.52 48.445 19.66 48.695 ;
      END
    ANTENNAGATEAREA 0.009 ;
    ANTENNADIFFAREA 0.035 ;
    END STOVB
  PIN TAA[3]
    DIRECTION INPUT ;
    USE SIGNAL ;
    SHAPE ABUTMENT ;
    PORT
      LAYER metal1 ;
      RECT 36.04 0.0 36.18 0.25 ;
      LAYER metal2 ;
      RECT 36.04 0.0 36.18 0.25 ;
      LAYER metal3 ;
      RECT 36.04 0.0 36.18 0.25 ;
      END
    ANTENNAGATEAREA 0.009 ;
    ANTENNADIFFAREA 0.035 ;
    END TAA[3]
  PIN EMAB[1]
    DIRECTION INPUT ;
    USE SIGNAL ;
    SHAPE ABUTMENT ;
    PORT
      LAYER metal3 ;
      RECT 19.02 48.445 19.16 48.695 ;
      LAYER metal2 ;
      RECT 19.02 48.445 19.16 48.695 ;
      LAYER metal1 ;
      RECT 19.02 48.445 19.16 48.695 ;
      END
    ANTENNAGATEAREA 0.009 ;
    ANTENNADIFFAREA 0.035 ;
    END EMAB[1]
  PIN TENA
    DIRECTION INPUT ;
    USE SIGNAL ;
    SHAPE ABUTMENT ;
    PORT
      LAYER metal1 ;
      RECT 36.29 0.0 36.43 0.25 ;
      LAYER metal2 ;
      RECT 36.29 0.0 36.43 0.25 ;
      LAYER metal3 ;
      RECT 36.29 0.0 36.43 0.25 ;
      END
    ANTENNAGATEAREA 0.009 ;
    ANTENNADIFFAREA 0.035 ;
    END TENA
  PIN EMAB[0]
    DIRECTION INPUT ;
    USE SIGNAL ;
    SHAPE ABUTMENT ;
    PORT
      LAYER metal3 ;
      RECT 18.77 48.445 18.91 48.695 ;
      LAYER metal2 ;
      RECT 18.77 48.445 18.91 48.695 ;
      LAYER metal1 ;
      RECT 18.77 48.445 18.91 48.695 ;
      END
    ANTENNAGATEAREA 0.009 ;
    ANTENNADIFFAREA 0.035 ;
    END EMAB[0]
  PIN AYA[1]
    DIRECTION OUTPUT ;
    USE SIGNAL ;
    SHAPE ABUTMENT ;
    PORT
      LAYER metal1 ;
      RECT 37.0 0.0 37.14 0.25 ;
      LAYER metal2 ;
      RECT 37.0 0.0 37.14 0.25 ;
      LAYER metal3 ;
      RECT 37.0 0.0 37.14 0.25 ;
      END
    ANTENNADIFFAREA 0.035 ;
    END AYA[1]
  PIN DB[7]
    DIRECTION INPUT ;
    USE SIGNAL ;
    SHAPE ABUTMENT ;
    PORT
      LAYER metal3 ;
      RECT 16.43 48.445 16.57 48.695 ;
      END
    ANTENNAGATEAREA 0.009 ;
    ANTENNADIFFAREA 0.035 ;
    END DB[7]
  PIN AYA[2]
    DIRECTION OUTPUT ;
    USE SIGNAL ;
    SHAPE ABUTMENT ;
    PORT
      LAYER metal1 ;
      RECT 37.25 0.0 37.39 0.25 ;
      LAYER metal2 ;
      RECT 37.25 0.0 37.39 0.25 ;
      LAYER metal3 ;
      RECT 37.25 0.0 37.39 0.25 ;
      END
    ANTENNADIFFAREA 0.035 ;
    END AYA[2]
  PIN DYB[7]
    DIRECTION OUTPUT ;
    USE SIGNAL ;
    SHAPE ABUTMENT ;
    PORT
      LAYER metal3 ;
      RECT 15.43 48.445 15.57 48.695 ;
      END
    ANTENNADIFFAREA 0.035 ;
    END DYB[7]
  PIN AYA[3]
    DIRECTION OUTPUT ;
    USE SIGNAL ;
    SHAPE ABUTMENT ;
    PORT
      LAYER metal1 ;
      RECT 37.6 0.0 37.74 0.25 ;
      LAYER metal2 ;
      RECT 37.6 0.0 37.74 0.25 ;
      LAYER metal3 ;
      RECT 37.6 0.0 37.74 0.25 ;
      END
    ANTENNADIFFAREA 0.035 ;
    END AYA[3]
  PIN TDB[7]
    DIRECTION INPUT ;
    USE SIGNAL ;
    SHAPE ABUTMENT ;
    PORT
      LAYER metal3 ;
      RECT 14.89 48.445 15.03 48.695 ;
      END
    ANTENNAGATEAREA 0.009 ;
    ANTENNADIFFAREA 0.035 ;
    END TDB[7]
  PIN BENA
    DIRECTION INPUT ;
    USE SIGNAL ;
    SHAPE ABUTMENT ;
    PORT
      LAYER metal1 ;
      RECT 40.01 0.0 40.15 0.25 ;
      LAYER metal2 ;
      RECT 40.01 0.0 40.15 0.25 ;
      LAYER metal3 ;
      RECT 40.01 0.0 40.15 0.25 ;
      END
    ANTENNAGATEAREA 0.009 ;
    ANTENNADIFFAREA 0.035 ;
    END BENA
  PIN TDB[6]
    DIRECTION INPUT ;
    USE SIGNAL ;
    SHAPE ABUTMENT ;
    PORT
      LAYER metal3 ;
      RECT 14.51 48.445 14.65 48.695 ;
      END
    ANTENNAGATEAREA 0.009 ;
    ANTENNADIFFAREA 0.035 ;
    END TDB[6]
  PIN EMASA
    DIRECTION INPUT ;
    USE SIGNAL ;
    SHAPE ABUTMENT ;
    PORT
      LAYER metal1 ;
      RECT 52.57 0.0 52.71 0.25 ;
      LAYER metal2 ;
      RECT 52.57 0.0 52.71 0.25 ;
      LAYER metal3 ;
      RECT 52.57 0.0 52.71 0.25 ;
      END
    ANTENNAGATEAREA 0.009 ;
    ANTENNADIFFAREA 0.035 ;
    END EMASA
  PIN DYB[6]
    DIRECTION OUTPUT ;
    USE SIGNAL ;
    SHAPE ABUTMENT ;
    PORT
      LAYER metal3 ;
      RECT 13.97 48.445 14.11 48.695 ;
      END
    ANTENNADIFFAREA 0.035 ;
    END DYB[6]
  PIN AYA[0]
    DIRECTION OUTPUT ;
    USE SIGNAL ;
    SHAPE ABUTMENT ;
    PORT
      LAYER metal1 ;
      RECT 55.18 0.0 55.32 0.25 ;
      LAYER metal2 ;
      RECT 55.18 0.0 55.32 0.25 ;
      LAYER metal3 ;
      RECT 55.18 0.0 55.32 0.25 ;
      END
    ANTENNADIFFAREA 0.035 ;
    END AYA[0]
  PIN DB[6]
    DIRECTION INPUT ;
    USE SIGNAL ;
    SHAPE ABUTMENT ;
    PORT
      LAYER metal3 ;
      RECT 12.97 48.445 13.11 48.695 ;
      END
    ANTENNAGATEAREA 0.009 ;
    ANTENNADIFFAREA 0.035 ;
    END DB[6]
  PIN TAA[0]
    DIRECTION INPUT ;
    USE SIGNAL ;
    SHAPE ABUTMENT ;
    PORT
      LAYER metal1 ;
      RECT 56.71 0.0 56.85 0.25 ;
      LAYER metal2 ;
      RECT 56.71 0.0 56.85 0.25 ;
      LAYER metal3 ;
      RECT 56.71 0.0 56.85 0.25 ;
      END
    ANTENNAGATEAREA 0.009 ;
    ANTENNADIFFAREA 0.035 ;
    END TAA[0]
  PIN DB[5]
    DIRECTION INPUT ;
    USE SIGNAL ;
    SHAPE ABUTMENT ;
    PORT
      LAYER metal3 ;
      RECT 12.53 48.445 12.67 48.695 ;
      END
    ANTENNAGATEAREA 0.009 ;
    ANTENNADIFFAREA 0.035 ;
    END DB[5]
  PIN AA[0]
    DIRECTION INPUT ;
    USE SIGNAL ;
    SHAPE ABUTMENT ;
    PORT
      LAYER metal1 ;
      RECT 57.21 0.0 57.35 0.25 ;
      LAYER metal2 ;
      RECT 57.21 0.0 57.35 0.25 ;
      LAYER metal3 ;
      RECT 57.21 0.0 57.35 0.25 ;
      END
    ANTENNAGATEAREA 0.009 ;
    ANTENNADIFFAREA 0.035 ;
    END AA[0]
  PIN DYB[5]
    DIRECTION OUTPUT ;
    USE SIGNAL ;
    SHAPE ABUTMENT ;
    PORT
      LAYER metal3 ;
      RECT 11.53 48.445 11.67 48.695 ;
      END
    ANTENNADIFFAREA 0.035 ;
    END DYB[5]
  PIN TQA[8]
    DIRECTION INPUT ;
    USE SIGNAL ;
    SHAPE ABUTMENT ;
    PORT
      LAYER metal1 ;
      RECT 58.8 0.0 58.94 0.25 ;
      LAYER metal2 ;
      RECT 58.8 0.0 58.94 0.25 ;
      LAYER metal3 ;
      RECT 58.8 0.0 58.94 0.25 ;
      END
    ANTENNAGATEAREA 0.009 ;
    ANTENNADIFFAREA 0.035 ;
    END TQA[8]
  PIN TDB[5]
    DIRECTION INPUT ;
    USE SIGNAL ;
    SHAPE ABUTMENT ;
    PORT
      LAYER metal3 ;
      RECT 10.99 48.445 11.13 48.695 ;
      END
    ANTENNAGATEAREA 0.009 ;
    ANTENNADIFFAREA 0.035 ;
    END TDB[5]
  PIN QA[8]
    DIRECTION OUTPUT ;
    USE SIGNAL ;
    SHAPE ABUTMENT ;
    PORT
      LAYER metal1 ;
      RECT 59.655 0.0 59.795 0.25 ;
      LAYER metal2 ;
      RECT 59.655 0.0 59.795 0.25 ;
      LAYER metal3 ;
      RECT 59.655 0.0 59.795 0.25 ;
      END
    ANTENNADIFFAREA 0.035 ;
    END QA[8]
  PIN TDB[4]
    DIRECTION INPUT ;
    USE SIGNAL ;
    SHAPE ABUTMENT ;
    PORT
      LAYER metal3 ;
      RECT 10.61 48.445 10.75 48.695 ;
      END
    ANTENNAGATEAREA 0.009 ;
    ANTENNADIFFAREA 0.035 ;
    END TDB[4]
  PIN QA[9]
    DIRECTION OUTPUT ;
    USE SIGNAL ;
    SHAPE ABUTMENT ;
    PORT
      LAYER metal1 ;
      RECT 61.345 0.0 61.485 0.25 ;
      LAYER metal2 ;
      RECT 61.345 0.0 61.485 0.25 ;
      LAYER metal3 ;
      RECT 61.345 0.0 61.485 0.25 ;
      END
    ANTENNADIFFAREA 0.035 ;
    END QA[9]
  PIN DYB[4]
    DIRECTION OUTPUT ;
    USE SIGNAL ;
    SHAPE ABUTMENT ;
    PORT
      LAYER metal3 ;
      RECT 10.07 48.445 10.21 48.695 ;
      END
    ANTENNADIFFAREA 0.035 ;
    END DYB[4]
  PIN TQA[9]
    DIRECTION INPUT ;
    USE SIGNAL ;
    SHAPE ABUTMENT ;
    PORT
      LAYER metal1 ;
      RECT 62.2 0.0 62.34 0.25 ;
      LAYER metal2 ;
      RECT 62.2 0.0 62.34 0.25 ;
      LAYER metal3 ;
      RECT 62.2 0.0 62.34 0.25 ;
      END
    ANTENNAGATEAREA 0.009 ;
    ANTENNADIFFAREA 0.035 ;
    END TQA[9]
  PIN DB[4]
    DIRECTION INPUT ;
    USE SIGNAL ;
    SHAPE ABUTMENT ;
    PORT
      LAYER metal3 ;
      RECT 9.07 48.445 9.21 48.695 ;
      END
    ANTENNAGATEAREA 0.009 ;
    ANTENNADIFFAREA 0.035 ;
    END DB[4]
  PIN TQA[10]
    DIRECTION INPUT ;
    USE SIGNAL ;
    SHAPE ABUTMENT ;
    PORT
      LAYER metal1 ;
      RECT 62.7 0.0 62.84 0.25 ;
      LAYER metal2 ;
      RECT 62.7 0.0 62.84 0.25 ;
      LAYER metal3 ;
      RECT 62.7 0.0 62.84 0.25 ;
      END
    ANTENNAGATEAREA 0.009 ;
    ANTENNADIFFAREA 0.035 ;
    END TQA[10]
  PIN DB[3]
    DIRECTION INPUT ;
    USE SIGNAL ;
    SHAPE ABUTMENT ;
    PORT
      LAYER metal3 ;
      RECT 8.63 48.445 8.77 48.695 ;
      END
    ANTENNAGATEAREA 0.009 ;
    ANTENNADIFFAREA 0.035 ;
    END DB[3]
  PIN QA[10]
    DIRECTION OUTPUT ;
    USE SIGNAL ;
    SHAPE ABUTMENT ;
    PORT
      LAYER metal1 ;
      RECT 63.555 0.0 63.695 0.25 ;
      LAYER metal2 ;
      RECT 63.555 0.0 63.695 0.25 ;
      LAYER metal3 ;
      RECT 63.555 0.0 63.695 0.25 ;
      END
    ANTENNADIFFAREA 0.035 ;
    END QA[10]
  PIN DYB[3]
    DIRECTION OUTPUT ;
    USE SIGNAL ;
    SHAPE ABUTMENT ;
    PORT
      LAYER metal3 ;
      RECT 7.63 48.445 7.77 48.695 ;
      END
    ANTENNADIFFAREA 0.035 ;
    END DYB[3]
  PIN QA[11]
    DIRECTION OUTPUT ;
    USE SIGNAL ;
    SHAPE ABUTMENT ;
    PORT
      LAYER metal1 ;
      RECT 65.245 0.0 65.385 0.25 ;
      LAYER metal2 ;
      RECT 65.245 0.0 65.385 0.25 ;
      LAYER metal3 ;
      RECT 65.245 0.0 65.385 0.25 ;
      END
    ANTENNADIFFAREA 0.035 ;
    END QA[11]
  PIN TDB[3]
    DIRECTION INPUT ;
    USE SIGNAL ;
    SHAPE ABUTMENT ;
    PORT
      LAYER metal3 ;
      RECT 7.09 48.445 7.23 48.695 ;
      END
    ANTENNAGATEAREA 0.009 ;
    ANTENNADIFFAREA 0.035 ;
    END TDB[3]
  PIN TQA[11]
    DIRECTION INPUT ;
    USE SIGNAL ;
    SHAPE ABUTMENT ;
    PORT
      LAYER metal1 ;
      RECT 66.1 0.0 66.24 0.25 ;
      LAYER metal2 ;
      RECT 66.1 0.0 66.24 0.25 ;
      LAYER metal3 ;
      RECT 66.1 0.0 66.24 0.25 ;
      END
    ANTENNAGATEAREA 0.009 ;
    ANTENNADIFFAREA 0.035 ;
    END TQA[11]
  PIN TDB[2]
    DIRECTION INPUT ;
    USE SIGNAL ;
    SHAPE ABUTMENT ;
    PORT
      LAYER metal3 ;
      RECT 6.71 48.445 6.85 48.695 ;
      END
    ANTENNAGATEAREA 0.009 ;
    ANTENNADIFFAREA 0.035 ;
    END TDB[2]
  PIN TQA[12]
    DIRECTION INPUT ;
    USE SIGNAL ;
    SHAPE ABUTMENT ;
    PORT
      LAYER metal1 ;
      RECT 66.6 0.0 66.74 0.25 ;
      LAYER metal2 ;
      RECT 66.6 0.0 66.74 0.25 ;
      LAYER metal3 ;
      RECT 66.6 0.0 66.74 0.25 ;
      END
    ANTENNAGATEAREA 0.009 ;
    ANTENNADIFFAREA 0.035 ;
    END TQA[12]
  PIN DYB[2]
    DIRECTION OUTPUT ;
    USE SIGNAL ;
    SHAPE ABUTMENT ;
    PORT
      LAYER metal3 ;
      RECT 6.17 48.445 6.31 48.695 ;
      END
    ANTENNADIFFAREA 0.035 ;
    END DYB[2]
  PIN QA[12]
    DIRECTION OUTPUT ;
    USE SIGNAL ;
    SHAPE ABUTMENT ;
    PORT
      LAYER metal1 ;
      RECT 67.455 0.0 67.595 0.25 ;
      LAYER metal2 ;
      RECT 67.455 0.0 67.595 0.25 ;
      LAYER metal3 ;
      RECT 67.455 0.0 67.595 0.25 ;
      END
    ANTENNADIFFAREA 0.035 ;
    END QA[12]
  PIN DB[2]
    DIRECTION INPUT ;
    USE SIGNAL ;
    SHAPE ABUTMENT ;
    PORT
      LAYER metal3 ;
      RECT 5.17 48.445 5.31 48.695 ;
      END
    ANTENNAGATEAREA 0.009 ;
    ANTENNADIFFAREA 0.035 ;
    END DB[2]
  PIN QA[13]
    DIRECTION OUTPUT ;
    USE SIGNAL ;
    SHAPE ABUTMENT ;
    PORT
      LAYER metal1 ;
      RECT 69.145 0.0 69.285 0.25 ;
      LAYER metal2 ;
      RECT 69.145 0.0 69.285 0.25 ;
      LAYER metal3 ;
      RECT 69.145 0.0 69.285 0.25 ;
      END
    ANTENNADIFFAREA 0.035 ;
    END QA[13]
  PIN DB[1]
    DIRECTION INPUT ;
    USE SIGNAL ;
    SHAPE ABUTMENT ;
    PORT
      LAYER metal3 ;
      RECT 4.73 48.445 4.87 48.695 ;
      END
    ANTENNAGATEAREA 0.009 ;
    ANTENNADIFFAREA 0.035 ;
    END DB[1]
  PIN TQA[13]
    DIRECTION INPUT ;
    USE SIGNAL ;
    SHAPE ABUTMENT ;
    PORT
      LAYER metal1 ;
      RECT 70.0 0.0 70.14 0.25 ;
      LAYER metal2 ;
      RECT 70.0 0.0 70.14 0.25 ;
      LAYER metal3 ;
      RECT 70.0 0.0 70.14 0.25 ;
      END
    ANTENNAGATEAREA 0.009 ;
    ANTENNADIFFAREA 0.035 ;
    END TQA[13]
  PIN DYB[1]
    DIRECTION OUTPUT ;
    USE SIGNAL ;
    SHAPE ABUTMENT ;
    PORT
      LAYER metal3 ;
      RECT 3.73 48.445 3.87 48.695 ;
      END
    ANTENNADIFFAREA 0.035 ;
    END DYB[1]
  PIN TQA[14]
    DIRECTION INPUT ;
    USE SIGNAL ;
    SHAPE ABUTMENT ;
    PORT
      LAYER metal1 ;
      RECT 70.5 0.0 70.64 0.25 ;
      LAYER metal2 ;
      RECT 70.5 0.0 70.64 0.25 ;
      LAYER metal3 ;
      RECT 70.5 0.0 70.64 0.25 ;
      END
    ANTENNAGATEAREA 0.009 ;
    ANTENNADIFFAREA 0.035 ;
    END TQA[14]
  PIN TDB[1]
    DIRECTION INPUT ;
    USE SIGNAL ;
    SHAPE ABUTMENT ;
    PORT
      LAYER metal3 ;
      RECT 3.19 48.445 3.33 48.695 ;
      END
    ANTENNAGATEAREA 0.009 ;
    ANTENNADIFFAREA 0.035 ;
    END TDB[1]
  PIN QA[14]
    DIRECTION OUTPUT ;
    USE SIGNAL ;
    SHAPE ABUTMENT ;
    PORT
      LAYER metal1 ;
      RECT 71.355 0.0 71.495 0.25 ;
      LAYER metal2 ;
      RECT 71.355 0.0 71.495 0.25 ;
      LAYER metal3 ;
      RECT 71.355 0.0 71.495 0.25 ;
      END
    ANTENNADIFFAREA 0.035 ;
    END QA[14]
  PIN TDB[0]
    DIRECTION INPUT ;
    USE SIGNAL ;
    SHAPE ABUTMENT ;
    PORT
      LAYER metal3 ;
      RECT 2.81 48.445 2.95 48.695 ;
      END
    ANTENNAGATEAREA 0.009 ;
    ANTENNADIFFAREA 0.035 ;
    END TDB[0]
  PIN QA[15]
    DIRECTION OUTPUT ;
    USE SIGNAL ;
    SHAPE ABUTMENT ;
    PORT
      LAYER metal1 ;
      RECT 73.045 0.0 73.185 0.25 ;
      LAYER metal2 ;
      RECT 73.045 0.0 73.185 0.25 ;
      LAYER metal3 ;
      RECT 73.045 0.0 73.185 0.25 ;
      END
    ANTENNADIFFAREA 0.035 ;
    END QA[15]
  PIN DYB[0]
    DIRECTION OUTPUT ;
    USE SIGNAL ;
    SHAPE ABUTMENT ;
    PORT
      LAYER metal3 ;
      RECT 2.27 48.445 2.41 48.695 ;
      END
    ANTENNADIFFAREA 0.035 ;
    END DYB[0]
  PIN TQA[15]
    DIRECTION INPUT ;
    USE SIGNAL ;
    SHAPE ABUTMENT ;
    PORT
      LAYER metal1 ;
      RECT 73.9 0.0 74.04 0.25 ;
      LAYER metal2 ;
      RECT 73.9 0.0 74.04 0.25 ;
      LAYER metal3 ;
      RECT 73.9 0.0 74.04 0.25 ;
      END
    ANTENNAGATEAREA 0.009 ;
    ANTENNADIFFAREA 0.035 ;
    END TQA[15]
  PIN DB[0]
    DIRECTION INPUT ;
    USE SIGNAL ;
    SHAPE ABUTMENT ;
    PORT
      LAYER metal3 ;
      RECT 1.27 48.445 1.41 48.695 ;
      END
    ANTENNAGATEAREA 0.009 ;
    ANTENNADIFFAREA 0.035 ;
    END DB[0]
  PIN VDDPE
    DIRECTION INOUT ;
    USE POWER ;
    PORT
      LAYER metal4 ;
      RECT 1.37 0.0 1.57 48.695 ;
      END
    PORT
      LAYER metal4 ;
      RECT 2.435 0.0 2.64 48.695 ;
      END
    PORT
      LAYER metal4 ;
      RECT 3.495 0.0 3.70 48.695 ;
      END
    PORT
      LAYER metal4 ;
      RECT 4.56 0.0 4.76 48.695 ;
      END
    PORT
      LAYER metal4 ;
      RECT 5.27 0.0 5.47 48.695 ;
      END
    PORT
      LAYER metal4 ;
      RECT 6.335 0.0 6.54 48.695 ;
      END
    PORT
      LAYER metal4 ;
      RECT 7.395 0.0 7.6 48.695 ;
      END
    PORT
      LAYER metal4 ;
      RECT 8.46 0.0 8.66 48.695 ;
      END
    PORT
      LAYER metal4 ;
      RECT 9.17 0.0 9.37 48.695 ;
      END
    PORT
      LAYER metal4 ;
      RECT 10.235 0.0 10.44 48.695 ;
      END
    PORT
      LAYER metal4 ;
      RECT 11.295 0.0 11.50 48.695 ;
      END
    PORT
      LAYER metal4 ;
      RECT 12.36 0.0 12.56 48.695 ;
      END
    PORT
      LAYER metal4 ;
      RECT 13.07 0.0 13.27 48.695 ;
      END
    PORT
      LAYER metal4 ;
      RECT 14.135 0.0 14.34 48.695 ;
      END
    PORT
      LAYER metal4 ;
      RECT 15.195 0.0 15.4 48.695 ;
      END
    PORT
      LAYER metal4 ;
      RECT 16.26 0.0 16.46 48.695 ;
      END
    PORT
      LAYER metal4 ;
      RECT 17.8 0.0 17.98 48.695 ;
      END
    PORT
      LAYER metal4 ;
      RECT 20.63 0.0 20.83 48.695 ;
      END
    PORT
      LAYER metal4 ;
      RECT 30.89 0.0 31.09 48.695 ;
      END
    PORT
      LAYER metal4 ;
      RECT 33.885 0.0 34.105 48.695 ;
      END
    PORT
      LAYER metal4 ;
      RECT 37.4 0.0 37.58 48.695 ;
      END
    PORT
      LAYER metal4 ;
      RECT 41.245 0.0 41.45 48.695 ;
      END
    PORT
      LAYER metal4 ;
      RECT 57.33 0.0 57.53 48.695 ;
      END
    PORT
      LAYER metal4 ;
      RECT 58.87 0.0 59.07 48.695 ;
      END
    PORT
      LAYER metal4 ;
      RECT 59.935 0.0 60.14 48.695 ;
      END
    PORT
      LAYER metal4 ;
      RECT 60.995 0.0 61.2 48.695 ;
      END
    PORT
      LAYER metal4 ;
      RECT 62.06 0.0 62.26 48.695 ;
      END
    PORT
      LAYER metal4 ;
      RECT 62.77 0.0 62.97 48.695 ;
      END
    PORT
      LAYER metal4 ;
      RECT 63.835 0.0 64.04 48.695 ;
      END
    PORT
      LAYER metal4 ;
      RECT 64.895 0.0 65.1 48.695 ;
      END
    PORT
      LAYER metal4 ;
      RECT 65.96 0.0 66.16 48.695 ;
      END
    PORT
      LAYER metal4 ;
      RECT 66.67 0.0 66.87 48.695 ;
      END
    PORT
      LAYER metal4 ;
      RECT 67.735 0.0 67.94 48.695 ;
      END
    PORT
      LAYER metal4 ;
      RECT 68.795 0.0 69.0 48.695 ;
      END
    PORT
      LAYER metal4 ;
      RECT 69.86 0.0 70.06 48.695 ;
      END
    PORT
      LAYER metal4 ;
      RECT 70.57 0.0 70.77 48.695 ;
      END
    PORT
      LAYER metal4 ;
      RECT 71.635 0.0 71.84 48.695 ;
      END
    PORT
      LAYER metal4 ;
      RECT 72.695 0.0 72.9 48.695 ;
      END
    PORT
      LAYER metal4 ;
      RECT 73.76 0.0 73.96 48.695 ;
      END
    END VDDPE
  PIN VDDCE
    DIRECTION INOUT ;
    USE POWER ;
    PORT
      LAYER metal4 ;
      RECT 1.015 0.0 1.22 48.695 ;
      END
    PORT
      LAYER metal4 ;
      RECT 2.08 0.0 2.28 48.695 ;
      END
    PORT
      LAYER metal4 ;
      RECT 3.85 0.0 4.05 48.695 ;
      END
    PORT
      LAYER metal4 ;
      RECT 4.915 0.0 5.12 48.695 ;
      END
    PORT
      LAYER metal4 ;
      RECT 5.98 0.0 6.18 48.695 ;
      END
    PORT
      LAYER metal4 ;
      RECT 7.75 0.0 7.95 48.695 ;
      END
    PORT
      LAYER metal4 ;
      RECT 8.815 0.0 9.02 48.695 ;
      END
    PORT
      LAYER metal4 ;
      RECT 9.88 0.0 10.08 48.695 ;
      END
    PORT
      LAYER metal4 ;
      RECT 11.65 0.0 11.85 48.695 ;
      END
    PORT
      LAYER metal4 ;
      RECT 12.715 0.0 12.92 48.695 ;
      END
    PORT
      LAYER metal4 ;
      RECT 13.78 0.0 13.98 48.695 ;
      END
    PORT
      LAYER metal4 ;
      RECT 15.55 0.0 15.75 48.695 ;
      END
    PORT
      LAYER metal4 ;
      RECT 16.615 0.0 16.82 48.695 ;
      END
    PORT
      LAYER metal4 ;
      RECT 18.13 0.0 18.33 48.695 ;
      END
    PORT
      LAYER metal4 ;
      RECT 37.73 0.0 37.93 48.695 ;
      END
    PORT
      LAYER metal4 ;
      RECT 57.0 0.0 57.18 48.695 ;
      END
    PORT
      LAYER metal4 ;
      RECT 58.515 0.0 58.72 48.695 ;
      END
    PORT
      LAYER metal4 ;
      RECT 59.58 0.0 59.78 48.695 ;
      END
    PORT
      LAYER metal4 ;
      RECT 61.35 0.0 61.55 48.695 ;
      END
    PORT
      LAYER metal4 ;
      RECT 62.415 0.0 62.62 48.695 ;
      END
    PORT
      LAYER metal4 ;
      RECT 63.48 0.0 63.68 48.695 ;
      END
    PORT
      LAYER metal4 ;
      RECT 65.25 0.0 65.45 48.695 ;
      END
    PORT
      LAYER metal4 ;
      RECT 66.315 0.0 66.52 48.695 ;
      END
    PORT
      LAYER metal4 ;
      RECT 67.38 0.0 67.58 48.695 ;
      END
    PORT
      LAYER metal4 ;
      RECT 69.15 0.0 69.35 48.695 ;
      END
    PORT
      LAYER metal4 ;
      RECT 70.215 0.0 70.42 48.695 ;
      END
    PORT
      LAYER metal4 ;
      RECT 71.28 0.0 71.48 48.695 ;
      END
    PORT
      LAYER metal4 ;
      RECT 73.05 0.0 73.25 48.695 ;
      END
    PORT
      LAYER metal4 ;
      RECT 74.115 0.0 74.32 48.695 ;
      END
    END VDDCE
  PIN VSSE
    DIRECTION INOUT ;
    USE GROUND ;
    PORT
      LAYER metal4 ;
      RECT 0.545 0.0 0.77 48.695 ;
      END
    PORT
      LAYER metal4 ;
      RECT 2.79 0.0 2.99 48.695 ;
      END
    PORT
      LAYER metal4 ;
      RECT 3.14 0.0 3.34 48.695 ;
      END
    PORT
      LAYER metal4 ;
      RECT 6.69 0.0 6.89 48.695 ;
      END
    PORT
      LAYER metal4 ;
      RECT 7.04 0.0 7.24 48.695 ;
      END
    PORT
      LAYER metal4 ;
      RECT 10.59 0.0 10.79 48.695 ;
      END
    PORT
      LAYER metal4 ;
      RECT 10.94 0.0 11.14 48.695 ;
      END
    PORT
      LAYER metal4 ;
      RECT 14.49 0.0 14.69 48.695 ;
      END
    PORT
      LAYER metal4 ;
      RECT 14.84 0.0 15.04 48.695 ;
      END
    PORT
      LAYER metal4 ;
      RECT 17.045 0.0 17.27 48.695 ;
      END
    PORT
      LAYER metal4 ;
      RECT 19.85 0.0 20.07 48.695 ;
      END
    PORT
      LAYER metal4 ;
      RECT 22.07 0.0 22.29 48.695 ;
      END
    PORT
      LAYER metal4 ;
      RECT 22.88 0.0 23.08 48.695 ;
      END
    PORT
      LAYER metal4 ;
      RECT 32.25 0.0 32.45 48.695 ;
      END
    PORT
      LAYER metal4 ;
      RECT 34.255 0.0 34.46 48.695 ;
      END
    PORT
      LAYER metal4 ;
      RECT 42.88 0.0 43.08 48.695 ;
      END
    PORT
      LAYER metal4 ;
      RECT 43.3 0.0 43.5 48.695 ;
      END
    PORT
      LAYER metal4 ;
      RECT 52.25 0.0 52.45 48.695 ;
      END
    PORT
      LAYER metal4 ;
      RECT 53.67 0.0 53.87 48.695 ;
      END
    PORT
      LAYER metal4 ;
      RECT 54.525 0.0 54.75 48.695 ;
      END
    PORT
      LAYER metal4 ;
      RECT 56.28 0.0 56.5 48.695 ;
      END
    PORT
      LAYER metal4 ;
      RECT 58.065 0.0 58.29 48.695 ;
      END
    PORT
      LAYER metal4 ;
      RECT 60.29 0.0 60.49 48.695 ;
      END
    PORT
      LAYER metal4 ;
      RECT 60.64 0.0 60.84 48.695 ;
      END
    PORT
      LAYER metal4 ;
      RECT 64.19 0.0 64.39 48.695 ;
      END
    PORT
      LAYER metal4 ;
      RECT 64.54 0.0 64.74 48.695 ;
      END
    PORT
      LAYER metal4 ;
      RECT 68.09 0.0 68.29 48.695 ;
      END
    PORT
      LAYER metal4 ;
      RECT 68.44 0.0 68.64 48.695 ;
      END
    PORT
      LAYER metal4 ;
      RECT 71.99 0.0 72.19 48.695 ;
      END
    PORT
      LAYER metal4 ;
      RECT 72.34 0.0 72.54 48.695 ;
      END
    PORT
      LAYER metal4 ;
      RECT 74.565 0.0 74.79 48.695 ;
      END
    END VSSE
  OBS
    #otc obstructions
    LAYER metal1 DESIGNRULEWIDTH 0.07 ;
    RECT 74.11 0.0 75.34 0.32 ;
    RECT 73.255 0.0 73.83 0.32 ;
    RECT 71.565 0.0 72.975 0.32 ;
    RECT 70.71 0.0 71.285 0.32 ;
    RECT 70.21 0.0 70.43 0.32 ;
    RECT 69.355 0.0 69.93 0.32 ;
    RECT 67.665 0.0 69.075 0.32 ;
    RECT 66.81 0.0 67.385 0.32 ;
    RECT 66.31 0.0 66.53 0.32 ;
    RECT 65.455 0.0 66.03 0.32 ;
    RECT 63.765 0.0 65.175 0.32 ;
    RECT 62.91 0.0 63.485 0.32 ;
    RECT 62.41 0.0 62.63 0.32 ;
    RECT 61.555 0.0 62.13 0.32 ;
    RECT 59.865 0.0 61.275 0.32 ;
    RECT 59.01 0.0 59.585 0.32 ;
    RECT 57.42 0.0 58.73 0.32 ;
    RECT 56.92 0.0 57.14 0.32 ;
    RECT 55.39 0.0 56.64 0.32 ;
    RECT 52.78 0.0 55.11 0.32 ;
    RECT 40.22 0.0 52.5 0.32 ;
    RECT 37.81 0.0 39.94 0.32 ;
    RECT 37.46 0.0 37.53 0.32 ;
    RECT 36.5 0.0 36.93 0.32 ;
    RECT 34.5 0.0 34.72 0.32 ;
    RECT 33.75 0.0 33.97 0.32 ;
    RECT 32.685 0.0 33.22 0.32 ;
    RECT 25.1 0.0 32.155 0.32 ;
    RECT 20.48 0.0 24.07 0.32 ;
    RECT 19.73 0.0 20.2 0.32 ;
    RECT 19.23 0.0 19.45 0.32 ;
    RECT 16.61 0.0 18.7 0.32 ;
    RECT 15.755 0.0 16.33 0.32 ;
    RECT 14.065 0.0 15.475 0.32 ;
    RECT 13.21 0.0 13.785 0.32 ;
    RECT 12.71 0.0 12.93 0.32 ;
    RECT 11.855 0.0 12.43 0.32 ;
    RECT 10.165 0.0 11.575 0.32 ;
    RECT 9.31 0.0 9.885 0.32 ;
    RECT 8.81 0.0 9.03 0.32 ;
    RECT 7.955 0.0 8.53 0.32 ;
    RECT 6.265 0.0 7.675 0.32 ;
    RECT 5.41 0.0 5.985 0.32 ;
    RECT 4.91 0.0 5.13 0.32 ;
    RECT 4.055 0.0 4.63 0.32 ;
    RECT 2.365 0.0 3.775 0.32 ;
    RECT 1.51 0.0 2.085 0.32 ;
    RECT 0.0 0.0 1.23 0.32 ;
    RECT 0.0 0.32 75.34 48.375 ;
    RECT 57.42 48.375 75.34 48.695 ;
    RECT 56.92 48.375 57.14 48.695 ;
    RECT 55.39 48.375 56.64 48.695 ;
    RECT 54.84 48.375 55.11 48.695 ;
    RECT 49.445 48.375 54.31 48.695 ;
    RECT 40.51 48.375 49.165 48.695 ;
    RECT 38.21 48.375 40.23 48.695 ;
    RECT 36.96 48.375 37.18 48.695 ;
    RECT 34.46 48.375 35.43 48.695 ;
    RECT 33.71 48.375 33.93 48.695 ;
    RECT 32.18 48.375 33.15 48.695 ;
    RECT 31.43 48.375 31.9 48.695 ;
    RECT 30.82 48.375 31.15 48.695 ;
    RECT 30.425 48.375 30.54 48.695 ;
    RECT 25.0 48.375 30.145 48.695 ;
    RECT 24.47 48.375 24.72 48.695 ;
    RECT 20.48 48.375 24.19 48.695 ;
    RECT 19.73 48.375 20.2 48.695 ;
    RECT 19.23 48.375 19.45 48.695 ;
    RECT 0.0 48.375 18.7 48.695 ;
    LAYER via1 ;
    RECT 0.0 0.0 75.34 48.695 ;
    LAYER metal2 DESIGNRULEWIDTH 0.07 ;
    RECT 74.11 0.0 75.34 0.32 ;
    RECT 73.255 0.0 73.83 0.32 ;
    RECT 71.565 0.0 72.975 0.32 ;
    RECT 70.71 0.0 71.285 0.32 ;
    RECT 70.21 0.0 70.43 0.32 ;
    RECT 69.355 0.0 69.93 0.32 ;
    RECT 67.665 0.0 69.075 0.32 ;
    RECT 66.81 0.0 67.385 0.32 ;
    RECT 66.31 0.0 66.53 0.32 ;
    RECT 65.455 0.0 66.03 0.32 ;
    RECT 63.765 0.0 65.175 0.32 ;
    RECT 62.91 0.0 63.485 0.32 ;
    RECT 62.41 0.0 62.63 0.32 ;
    RECT 61.555 0.0 62.13 0.32 ;
    RECT 59.865 0.0 61.275 0.32 ;
    RECT 59.01 0.0 59.585 0.32 ;
    RECT 57.42 0.0 58.73 0.32 ;
    RECT 56.92 0.0 57.14 0.32 ;
    RECT 55.39 0.0 56.64 0.32 ;
    RECT 52.78 0.0 55.11 0.32 ;
    RECT 40.22 0.0 52.5 0.32 ;
    RECT 37.81 0.0 39.94 0.32 ;
    RECT 37.46 0.0 37.53 0.32 ;
    RECT 36.5 0.0 36.93 0.32 ;
    RECT 34.5 0.0 34.72 0.32 ;
    RECT 33.75 0.0 33.97 0.32 ;
    RECT 32.685 0.0 33.22 0.32 ;
    RECT 25.1 0.0 32.155 0.32 ;
    RECT 20.48 0.0 24.07 0.32 ;
    RECT 19.73 0.0 20.2 0.32 ;
    RECT 19.23 0.0 19.45 0.32 ;
    RECT 16.61 0.0 18.7 0.32 ;
    RECT 15.755 0.0 16.33 0.32 ;
    RECT 14.065 0.0 15.475 0.32 ;
    RECT 13.21 0.0 13.785 0.32 ;
    RECT 12.71 0.0 12.93 0.32 ;
    RECT 11.855 0.0 12.43 0.32 ;
    RECT 10.165 0.0 11.575 0.32 ;
    RECT 9.31 0.0 9.885 0.32 ;
    RECT 8.81 0.0 9.03 0.32 ;
    RECT 7.955 0.0 8.53 0.32 ;
    RECT 6.265 0.0 7.675 0.32 ;
    RECT 5.41 0.0 5.985 0.32 ;
    RECT 4.91 0.0 5.13 0.32 ;
    RECT 4.055 0.0 4.63 0.32 ;
    RECT 2.365 0.0 3.775 0.32 ;
    RECT 1.51 0.0 2.085 0.32 ;
    RECT 0.0 0.0 1.23 0.32 ;
    RECT 0.0 0.32 75.34 48.375 ;
    RECT 57.42 48.375 75.34 48.695 ;
    RECT 56.92 48.375 57.14 48.695 ;
    RECT 55.39 48.375 56.64 48.695 ;
    RECT 54.84 48.375 55.11 48.695 ;
    RECT 49.445 48.375 54.31 48.695 ;
    RECT 40.51 48.375 49.165 48.695 ;
    RECT 38.21 48.375 40.23 48.695 ;
    RECT 36.96 48.375 37.18 48.695 ;
    RECT 34.46 48.375 35.43 48.695 ;
    RECT 33.71 48.375 33.93 48.695 ;
    RECT 32.18 48.375 33.15 48.695 ;
    RECT 31.43 48.375 31.9 48.695 ;
    RECT 30.82 48.375 31.15 48.695 ;
    RECT 30.425 48.375 30.54 48.695 ;
    RECT 25.0 48.375 30.145 48.695 ;
    RECT 24.47 48.375 24.72 48.695 ;
    RECT 20.48 48.375 24.19 48.695 ;
    RECT 19.73 48.375 20.2 48.695 ;
    RECT 19.23 48.375 19.45 48.695 ;
    RECT 0.0 48.375 18.7 48.695 ;
    LAYER via2 ;
    RECT 0.0 0.0 75.34 48.695 ;
    LAYER metal3 DESIGNRULEWIDTH 0.07 ;
    RECT 74.11 0.0 75.34 0.32 ;
    RECT 73.255 0.0 73.83 0.32 ;
    RECT 71.565 0.0 72.975 0.32 ;
    RECT 70.71 0.0 71.285 0.32 ;
    RECT 70.21 0.0 70.43 0.32 ;
    RECT 69.355 0.0 69.93 0.32 ;
    RECT 67.665 0.0 69.075 0.32 ;
    RECT 66.81 0.0 67.385 0.32 ;
    RECT 66.31 0.0 66.53 0.32 ;
    RECT 65.455 0.0 66.03 0.32 ;
    RECT 63.765 0.0 65.175 0.32 ;
    RECT 62.91 0.0 63.485 0.32 ;
    RECT 62.41 0.0 62.63 0.32 ;
    RECT 61.555 0.0 62.13 0.32 ;
    RECT 59.865 0.0 61.275 0.32 ;
    RECT 59.01 0.0 59.585 0.32 ;
    RECT 57.42 0.0 58.73 0.32 ;
    RECT 56.92 0.0 57.14 0.32 ;
    RECT 55.39 0.0 56.64 0.32 ;
    RECT 52.78 0.0 55.11 0.32 ;
    RECT 40.22 0.0 52.5 0.32 ;
    RECT 37.81 0.0 39.94 0.32 ;
    RECT 37.46 0.0 37.53 0.32 ;
    RECT 36.5 0.0 36.93 0.32 ;
    RECT 34.5 0.0 34.72 0.32 ;
    RECT 33.75 0.0 33.97 0.32 ;
    RECT 32.685 0.0 33.22 0.32 ;
    RECT 25.1 0.0 32.155 0.32 ;
    RECT 20.48 0.0 24.07 0.32 ;
    RECT 19.73 0.0 20.2 0.32 ;
    RECT 19.23 0.0 19.45 0.32 ;
    RECT 16.61 0.0 18.7 0.32 ;
    RECT 15.755 0.0 16.33 0.32 ;
    RECT 14.065 0.0 15.475 0.32 ;
    RECT 13.21 0.0 13.785 0.32 ;
    RECT 12.71 0.0 12.93 0.32 ;
    RECT 11.855 0.0 12.43 0.32 ;
    RECT 10.165 0.0 11.575 0.32 ;
    RECT 9.31 0.0 9.885 0.32 ;
    RECT 8.81 0.0 9.03 0.32 ;
    RECT 7.955 0.0 8.53 0.32 ;
    RECT 6.265 0.0 7.675 0.32 ;
    RECT 5.41 0.0 5.985 0.32 ;
    RECT 4.91 0.0 5.13 0.32 ;
    RECT 4.055 0.0 4.63 0.32 ;
    RECT 2.365 0.0 3.775 0.32 ;
    RECT 1.51 0.0 2.085 0.32 ;
    RECT 0.0 0.0 1.23 0.32 ;
    RECT 0.0 0.32 75.34 48.375 ;
    RECT 74.14 48.375 75.34 48.695 ;
    RECT 73.14 48.375 73.86 48.695 ;
    RECT 72.6 48.375 72.86 48.695 ;
    RECT 72.22 48.375 72.32 48.695 ;
    RECT 71.68 48.375 71.94 48.695 ;
    RECT 70.68 48.375 71.4 48.695 ;
    RECT 70.24 48.375 70.4 48.695 ;
    RECT 69.24 48.375 69.96 48.695 ;
    RECT 68.7 48.375 68.96 48.695 ;
    RECT 68.32 48.375 68.42 48.695 ;
    RECT 67.78 48.375 68.04 48.695 ;
    RECT 66.78 48.375 67.5 48.695 ;
    RECT 66.34 48.375 66.5 48.695 ;
    RECT 65.34 48.375 66.06 48.695 ;
    RECT 64.8 48.375 65.06 48.695 ;
    RECT 64.42 48.375 64.52 48.695 ;
    RECT 63.88 48.375 64.14 48.695 ;
    RECT 62.88 48.375 63.6 48.695 ;
    RECT 62.44 48.375 62.6 48.695 ;
    RECT 61.44 48.375 62.16 48.695 ;
    RECT 60.9 48.375 61.16 48.695 ;
    RECT 60.52 48.375 60.62 48.695 ;
    RECT 59.98 48.375 60.24 48.695 ;
    RECT 58.98 48.375 59.7 48.695 ;
    RECT 57.42 48.375 58.7 48.695 ;
    RECT 56.92 48.375 57.14 48.695 ;
    RECT 55.39 48.375 56.64 48.695 ;
    RECT 54.84 48.375 55.11 48.695 ;
    RECT 49.445 48.375 54.31 48.695 ;
    RECT 40.51 48.375 49.165 48.695 ;
    RECT 38.21 48.375 40.23 48.695 ;
    RECT 36.96 48.375 37.18 48.695 ;
    RECT 34.46 48.375 35.43 48.695 ;
    RECT 33.71 48.375 33.93 48.695 ;
    RECT 32.18 48.375 33.15 48.695 ;
    RECT 31.43 48.375 31.9 48.695 ;
    RECT 30.82 48.375 31.15 48.695 ;
    RECT 30.425 48.375 30.54 48.695 ;
    RECT 25.0 48.375 30.145 48.695 ;
    RECT 24.47 48.375 24.72 48.695 ;
    RECT 20.48 48.375 24.19 48.695 ;
    RECT 19.73 48.375 20.2 48.695 ;
    RECT 19.23 48.375 19.45 48.695 ;
    RECT 16.64 48.375 18.7 48.695 ;
    RECT 15.64 48.375 16.36 48.695 ;
    RECT 15.1 48.375 15.36 48.695 ;
    RECT 14.72 48.375 14.82 48.695 ;
    RECT 14.18 48.375 14.44 48.695 ;
    RECT 13.18 48.375 13.9 48.695 ;
    RECT 12.74 48.375 12.9 48.695 ;
    RECT 11.74 48.375 12.46 48.695 ;
    RECT 11.2 48.375 11.46 48.695 ;
    RECT 10.82 48.375 10.92 48.695 ;
    RECT 10.28 48.375 10.54 48.695 ;
    RECT 9.28 48.375 10.0 48.695 ;
    RECT 8.84 48.375 9.0 48.695 ;
    RECT 7.84 48.375 8.56 48.695 ;
    RECT 7.3 48.375 7.56 48.695 ;
    RECT 6.92 48.375 7.02 48.695 ;
    RECT 6.38 48.375 6.64 48.695 ;
    RECT 5.38 48.375 6.1 48.695 ;
    RECT 4.94 48.375 5.1 48.695 ;
    RECT 3.94 48.375 4.66 48.695 ;
    RECT 3.4 48.375 3.66 48.695 ;
    RECT 3.02 48.375 3.12 48.695 ;
    RECT 2.48 48.375 2.74 48.695 ;
    RECT 1.48 48.375 2.2 48.695 ;
    RECT 0.0 48.375 1.2 48.695 ;
    LAYER via3 ;
    RECT 0.0 0.0 75.34 48.695 ;
    LAYER metal4 DESIGNRULEWIDTH 0.07 ;
    RECT 74.935 0.0 75.26 48.695 ;
    RECT 73.40 0.0 73.61 48.695 ;
    RECT 70.92 0.0 71.13 48.695 ;
    RECT 69.50 0.0 69.71 48.695 ;
    RECT 67.02 0.0 67.23 48.695 ;
    RECT 65.60 0.0 65.81 48.695 ;
    RECT 63.12 0.0 63.33 48.695 ;
    RECT 61.70 0.0 61.91 48.695 ;
    RECT 59.22 0.0 59.43 48.695 ;
    RECT 57.68 0.0 57.915 48.695 ;
    RECT 56.65 0.0 56.85 48.695 ;
    RECT 54.895 0.0 56.13 48.695 ;
    RECT 54.02 0.0 54.375 48.695 ;
    RECT 52.60 0.0 53.52 48.695 ;
    RECT 43.65 0.0 52.10 48.695 ;
    RECT 41.595 0.0 42.73 48.695 ;
    RECT 38.08 0.0 41.095 48.695 ;
    RECT 34.605 0.0 37.25 48.695 ;
    RECT 32.60 0.0 33.735 48.695 ;
    RECT 31.24 0.0 32.10 48.695 ;
    RECT 23.23 0.0 30.74 48.695 ;
    RECT 22.44 0.0 22.73 48.695 ;
    RECT 20.98 0.0 21.92 48.695 ;
    RECT 20.22 0.0 20.48 48.695 ;
    RECT 18.48 0.0 19.70 48.695 ;
    RECT 17.415 0.0 17.65 48.695 ;
    RECT 15.9  0.0 16.11 48.695 ;
    RECT 13.42 0.0 13.63 48.695 ;
    RECT 12.0  0.0 12.21 48.695 ;
    RECT 9.52 0.0 9.73 48.695 ;
    RECT 8.1  0.0 8.31 48.695 ;
    RECT 5.62 0.0 5.83 48.695 ;
    RECT 4.20 0.0 4.41 48.695 ;
    RECT 1.72 0.0 1.93 48.695 ;
    RECT 0.0 0.0 0.395 48.695 ;
    END
  END rf_2p_hse

END LIBRARY

